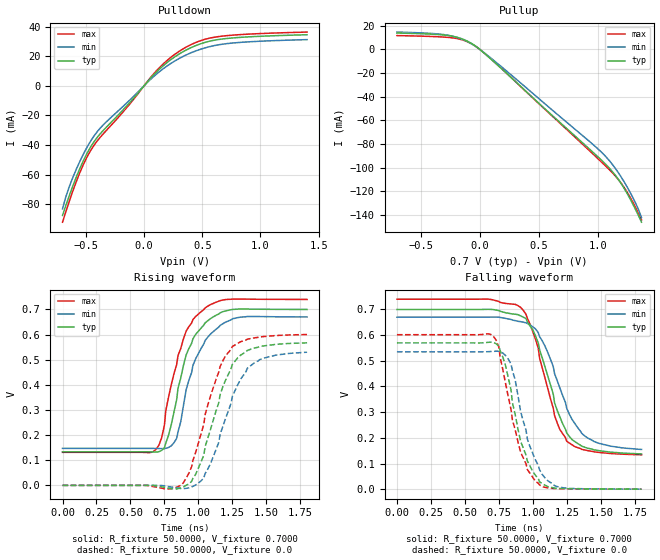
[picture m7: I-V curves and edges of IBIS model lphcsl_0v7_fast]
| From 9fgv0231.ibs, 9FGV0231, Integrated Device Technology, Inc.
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[Model]   lphcsl_0v7_fast
Model_type Output
Polarity   Non-Inverting
Enable   Active-High
Vmeas =  0.4000V
Cref =   2.0000pF
Rref =   0.0
Vref =   0.4000V
C_comp   1.1000pF   1.0000pF   1.2000pF
[Temperature Range]   25.0000   75.0000   0.0
[Voltage Range]   0.7000V   0.6700V   0.7400V
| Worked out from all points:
|   slope of the pulldown table from 0 to 0.105 V, typ, clamps not added: 11.5 ohm
|   slope of the pullup table from 0 to 0.105 V, typ, clamps not added: 11.5 ohm
|   rising waveform, R_fixture 50.0000, V_fixture 0.7000: 20-80 % time 161ps typ, 172ps min, 163ps max; typ from 0.134 V to 0.7 V
|   rising waveform, R_fixture 50.0000, V_fixture 0.0: 20-80 % time 196ps typ, 209ps min, 193ps max; typ from 0 V to 0.567 V
|   falling waveform, R_fixture 50.0000, V_fixture 0.7000: 20-80 % time 198ps typ, 226ps min, 186ps max; typ from 0.7 V to 0.138 V
|   falling waveform, R_fixture 50.0000, V_fixture 0.0: 20-80 % time 148ps typ, 157ps min, 158ps max; typ from 0.57 V to 0 V
[Pulldown]
|Voltage   I(typ)   I(min)   I(max)
-700mV    -87.46mA   -83.06mA   -92.05mA
-640mV    -73.75mA   -67.7mA    -77.54mA
-580mV    -61.27mA   -56.03mA   -64.32mA
-490mV    -45.66mA   -41.53mA   -48.1mA
-430mV    -37.82mA   -33.91mA   -40.19mA
-340mV    -29.28mA   -25.55mA   -31.55mA
50mV      4.609mA    3.896mA    5.041mA
230mV     17.65mA    15.08mA    19.19mA
410mV     26mA       22.5mA     28.05mA
590mV     30.57mA    26.92mA    32.6mA
860mV     32.86mA    29.49mA    34.71mA
1.4V      34.46mA    31.17mA    36.26mA
[Pullup]
|Voltage   I(typ)   I(min)   I(max)
-700mV    13.69mA    14.51mA    11.54mA
-370mV    12.52mA    13.09mA    10.63mA
-220mV    10.82mA    10.77mA    9.497mA
-100mV    6.649mA    6.27mA     6.197mA
-10mV     821.9uA    747.4uA    796.9uA
290mV     -26.07mA   -23.65mA   -26.13mA
1.04V     -94.6mA    -87.89mA   -96.18mA
1.13V     -104.2mA   -98.2mA    -105.1mA
1.22V     -117.1mA   -111.6mA   -116.4mA
1.31V     -133.6mA   -128mA     -131.9mA
1.34V     -139.7mA   -134.5mA   -137.9mA
1.37V     -146.2mA   -142.3mA   -144.3mA
[Ramp]
| variable   typ   min   max
dV/dt_r  0.3404/0.1944n   0.3179/0.2062n   0.3601/0.1919n
dV/dt_f  0.3375/0.1959n   0.3091/0.2218n   0.3636/0.1855n
R_load = 50.0000
[Rising Waveform]
R_fixture= 50.0000
V_fixture= 0.7000
V_fixture_min= 0.6700
V_fixture_max= 0.7400
|time   V(typ)   V(min)   V(max)
0s        133.6mV    147.2mV    131.3mV
640ps     133.6mV    147.2mV    130.1mV
730ps     139.3mV    146.3mV    190.1mV
780ps     199mV      150.6mV    350.3mV
840ps     340.8mV    187.2mV    480.7mV
910ps     519.1mV    380.8mV    613.9mV
980ps     601mV      504mV      672.2mV
1.09ns    664.1mV    602.6mV    719.7mV
1.25ns    700.2mV    662.9mV    741.4mV
1.8ns     700.2mV    670.4mV    740.1mV
[Rising Waveform]
R_fixture= 50.0000
V_fixture= 0.0
V_fixture_min= 0.0
V_fixture_max= 0.0
|time   V(typ)   V(min)   V(max)
0s        0V         0V         0V
870ps     -10.37mV   -12.56mV   -102.8uV
950ps     16.06mV    -6.886mV   73.86mV
1.04ns    120.1mV    29.51mV    243.5mV
1.07ns    189.3mV    65.39mV    320.9mV
1.16ns    361.1mV    203.1mV    473.5mV
1.25ns    481.3mV    354.1mV    552.7mV
1.36ns    537mV      466mV      581.7mV
1.42ns    547.6mV    490.7mV    587.7mV
1.8ns     567.3mV    529.9mV    600.2mV
[Falling Waveform]
R_fixture= 50.0000
V_fixture= 0.7000
V_fixture_min= 0.6700
V_fixture_max= 0.7400
|time   V(typ)   V(min)   V(max)
0s        700mV      670mV      740mV
670ps     700.5mV    670.1mV    740.3mV
910ps     675.2mV    652.5mV    708.4mV
950ps     664.7mV    647.9mV    680.9mV
1.04ns    569.5mV    609.9mV    549.2mV
1.16ns    336.4mV    450.4mV    286.8mV
1.25ns    219mV      314.3mV    186.5mV
1.36ns    167.7mV    217.5mV    155.1mV
1.45ns    153.3mV    185.8mV    145.6mV
1.8ns     137.5mV    154.9mV    134mV
[Falling Waveform]
R_fixture= 50.0000
V_fixture= 0.0
V_fixture_min= 0.0
V_fixture_max= 0.0
|time   V(typ)   V(min)   V(max)
0s        569.8mV    535.1mV    601.7mV
710ps     571.3mV    536.8mV    595.1mV
750ps     557.2mV    537.2mV    554.1mV
840ps     385.3mV    487mV      309.2mV
850ps     337.3mV    461.6mV    269.4mV
910ps     187mV      302.9mV    144.2mV
960ps     109.8mV    195mV      76.57mV
1.07ns    20.83mV    57.2mV     9.671mV
1.22ns    2.418mV    5.906mV    1.792mV
1.8ns     214uV      374.6uV    155.2uV
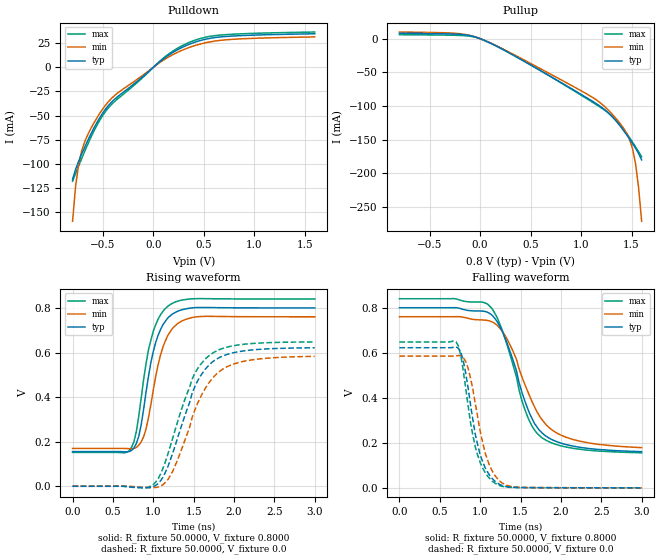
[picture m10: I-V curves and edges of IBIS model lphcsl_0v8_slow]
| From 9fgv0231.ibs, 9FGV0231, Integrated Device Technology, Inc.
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[Model]   lphcsl_0v8_slow
Model_type Output
Polarity   Non-Inverting
Enable   Active-High
Vmeas =  0.4000V
Cref =   2.0000pF
Rref =   0.0
Vref =   0.4000V
C_comp   1.1000pF   1.0000pF   1.2000pF
[Temperature Range]   25.0000   75.0000   0.0
[Voltage Range]   0.8000V   0.7600V   0.8400V
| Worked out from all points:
|   slope of the pulldown table from 0 to 0.12 V, typ, clamps not added: 11.7 ohm
|   slope of the pullup table from 0 to 0.12 V, typ, clamps not added: 14.9 ohm
|   rising waveform, R_fixture 50.0000, V_fixture 0.8000: 20-80 % time 200ps typ, 210ps min, 198ps max; typ from 0.156 V to 0.8 V
|   rising waveform, R_fixture 50.0000, V_fixture 0.0: 20-80 % time 372ps typ, 395ps min, 365ps max; typ from 0 V to 0.621 V
|   falling waveform, R_fixture 50.0000, V_fixture 0.8000: 20-80 % time 369ps typ, 426ps min, 346ps max; typ from 0.8 V to 0.161 V
|   falling waveform, R_fixture 50.0000, V_fixture 0.0: 20-80 % time 196ps typ, 206ps min, 192ps max; typ from 0.622 V to 0 V
[Pulldown]
|Voltage   I(typ)   I(min)   I(max)
-800mV    -116.2mA   -159.6mA   -118.1mA
-770mV    -105.7mA   -123.3mA   -110mA
-740mV    -97.45mA   -100.6mA   -102.3mA
-710mV    -89.96mA   -86.62mA   -94.65mA
-680mV    -82.85mA   -77.23mA   -87.18mA
-590mV    -63.31mA   -57.9mA    -66.46mA
-500mV    -47.21mA   -42.99mA   -49.67mA
-350mV    -30.12mA   -26.35mA   -32.41mA
130mV     11.06mA    9.39mA     12.07mA
430mV     26.68mA    23.13mA    28.76mA
760mV     32.3mA     28.88mA    34.18mA
1.6V      34.82mA    31.54mA    36.61mA
[Pullup]
|Voltage   I(typ)   I(min)   I(max)
-800mV    8.048mA    9.895mA    5.936mA
-230mV    6.658mA    7.836mA    4.986mA
10mV      -610.1uA   -603.7uA   -546.5uA
400mV     -30.63mA   -28.86mA   -30.13mA
1.18V     -99.5mA    -94.17mA   -100.9mA
1.36V     -124.8mA   -121.1mA   -123.5mA
1.42V     -136.4mA   -133mA     -134.6mA
1.48V     -149.1mA   -149.7mA   -147.2mA
1.51V     -155.9mA   -163.7mA   -153.9mA
1.54V     -163mA     -186.3mA   -161mA
1.57V     -170.8mA   -221.5mA   -168.2mA
1.6V      -180.3mA   -271.5mA   -175.6mA
[Ramp]
| variable   typ   min   max
dV/dt_r  0.3728/0.3923n   0.3497/0.4152n   0.3884/0.3847n
dV/dt_f  0.3835/0.3888n   0.3488/0.4461n   0.4106/0.3660n
R_load = 50.0000
[Rising Waveform]
R_fixture= 50.0000
V_fixture= 0.8000
V_fixture_min= 0.7600
V_fixture_max= 0.8400
|time   V(typ)   V(min)   V(max)
0s        155.5mV    169.8mV    151.7mV
730ps     160.5mV    168.1mV    174.2mV
790ps     191.7mV    174.2mV    245.5mV
880ps     345.2mV    221.9mV    478.6mV
940ps     492.3mV    307.8mV    611.5mV
1ns       604.4mV    431.8mV    695.9mV
1.09ns    703.3mV    589.3mV    769.4mV
1.21ns    764.5mV    693.4mV    815.4mV
1.55ns    801.8mV    760.6mV    841.7mV
3ns       800mV      760.1mV    840mV
[Rising Waveform]
R_fixture= 50.0000
V_fixture= 0.0
V_fixture_min= 0.0
V_fixture_max= 0.0
|time   V(typ)   V(min)   V(max)
0s        0V         0V         0V
1ns       -1.534mV   -6.251mV   7.313mV
1.12ns    40.5mV     7.13mV     80.44mV
1.24ns    148mV      67.05mV    215.2mV
1.48ns    416.1mV    307.4mV    479.7mV
1.61ns    508.3mV    417.9mV    556.9mV
1.76ns    565.2mV    495.3mV    602.8mV
1.91ns    590.9mV    535.7mV    623.8mV
2.15ns    608.6mV    562.6mV    638.1mV
3ns       621.3mV    582.9mV    647.4mV
[Falling Waveform]
R_fixture= 50.0000
V_fixture= 0.8000
V_fixture_min= 0.7600
V_fixture_max= 0.8400
|time   V(typ)   V(min)   V(max)
0s        800mV      760mV      840mV
1.09ns    780.1mV    743.3mV    816.4mV
1.21ns    738.8mV    721.9mV    756.9mV
1.33ns    645.9mV    662.9mV    639mV
1.55ns    389.2mV    463mV      351.4mV
1.64ns    309.7mV    385mV      275.7mV
1.73ns    257.3mV    322mV      233.7mV
1.88ns    215.9mV    259.8mV    200.5mV
2.12ns    187.6mV    218.1mV    177.5mV
3ns       160.9mV    178.7mV    155.7mV
[Falling Waveform]
R_fixture= 50.0000
V_fixture= 0.0
V_fixture_min= 0.0
V_fixture_max= 0.0
|time   V(typ)   V(min)   V(max)
0s        622.3mV    585.1mV    648mV
700ps     626mV      586.4mV    649mV
760ps     602.8mV    586.3mV    588.6mV
850ps     444.3mV    532.1mV    366.5mV
910ps     301.8mV    436mV      232.6mV
970ps     190.1mV    312.7mV    144mV
1.06ns    90.53mV    156.7mV    69.25mV
1.21ns    21.61mV    42.22mV    14.51mV
1.48ns    1.586mV    2.449mV    1.326mV
3ns       115.2uV    172.4uV    91.15uV
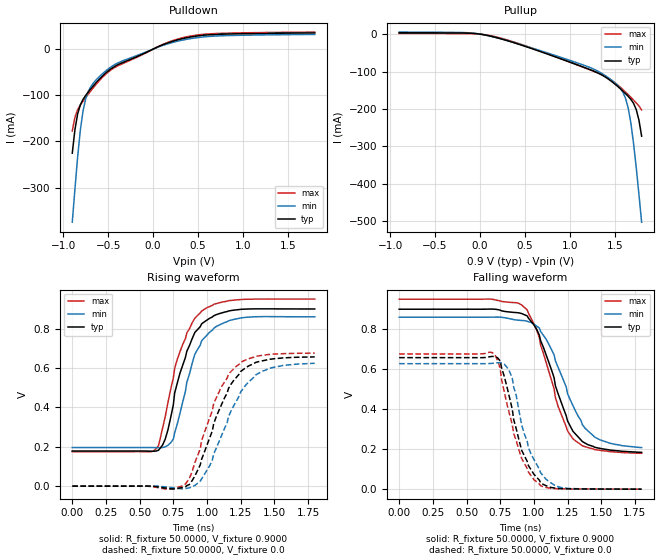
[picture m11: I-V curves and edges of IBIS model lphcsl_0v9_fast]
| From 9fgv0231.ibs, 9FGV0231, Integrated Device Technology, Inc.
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[Model]   lphcsl_0v9_fast
Model_type Output
Polarity   Non-Inverting
Enable   Active-High
Vmeas =  0.4000V
Cref =   2.0000pF
Rref =   0.0
Vref =   0.4000V
C_comp   1.1000pF   1.0000pF   1.2000pF
[Temperature Range]   25.0000   75.0000   0.0
[Voltage Range]   0.9000V   0.8600V   0.9500V
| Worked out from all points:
|   slope of the pulldown table from 0 to 0.135 V, typ, clamps not added: 11.8 ohm
|   slope of the pullup table from 0 to 0.135 V, typ, clamps not added: 21.1 ohm
|   rising waveform, R_fixture 50.0000, V_fixture 0.9000: 20-80 % time 172ps typ, 171ps min, 183ps max; typ from 0.178 V to 0.9 V
|   rising waveform, R_fixture 50.0000, V_fixture 0.0: 20-80 % time 228ps typ, 238ps min, 223ps max; typ from 0 V to 0.656 V
|   falling waveform, R_fixture 50.0000, V_fixture 0.9000: 20-80 % time 216ps typ, 245ps min, 207ps max; typ from 0.9 V to 0.184 V
|   falling waveform, R_fixture 50.0000, V_fixture 0.0: 20-80 % time 159ps typ, 165ps min, 162ps max; typ from 0.658 V to 0 V
[Pulldown]
|Voltage   I(typ)   I(min)   I(max)
-900mV    -225.6mA   -375.2mA   -177.4mA
-870mV    -174mA     -302.4mA   -147.5mA
-840mV    -140.3mA   -233.2mA   -131.2mA
-810mV    -120.8mA   -175.3mA   -121mA
-780mV    -109mA     -133.7mA   -112.8mA
-750mV    -100.2mA   -107mA     -105mA
-720mV    -92.49mA   -90.68mA   -97.27mA
-660mV    -78.35mA   -72.31mA   -82.41mA
-510mV    -48.82mA   -44.52mA   -51.32mA
90mV      7.972mA    6.753mA    8.709mA
390mV     25.27mA    21.84mA    27.29mA
1.8V      35.12mA    31.84mA    36.91mA
[Pullup]
|Voltage   I(typ)   I(min)   I(max)
-900mV    3.551mA    5.396mA    1.738mA
-150mV    2.686mA    3.793mA    1.334mA
150mV     -7.265mA   -7.528mA   -5.877mA
1.17V     -89.91mA   -84.27mA   -90.34mA
1.47V     -127.4mA   -123.7mA   -124.2mA
1.59V     -152mA     -154.4mA   -147.8mA
1.62V     -158.9mA   -170.8mA   -154.6mA
1.65V     -166.1mA   -197.2mA   -161.6mA
1.68V     -174.3mA   -237.1mA   -168.8mA
1.74V     -201.6mA   -356.7mA   -183.8mA
1.77V     -229.7mA   -428mA     -192mA
1.8V      -272.8mA   -502.6mA   -202.5mA
[Ramp]
| variable   typ   min   max
dV/dt_r  0.3939/0.2244n   0.3744/0.2413n   0.4055/0.2185n
dV/dt_f  0.4294/0.2165n   0.3912/0.2409n   0.4624/0.2039n
R_load = 50.0000
[Rising Waveform]
R_fixture= 50.0000
V_fixture= 0.9000
V_fixture_min= 0.8600
V_fixture_max= 0.9500
|time   V(typ)   V(min)   V(max)
0s        178.3mV    195.9mV    175.1mV
620ps     177.9mV    195.5mV    188.5mV
690ps     238.7mV    199.7mV    352.1mV
750ps     412.4mV    238.8mV    548.8mV
760ps     472.7mV    270.1mV    598.4mV
850ps     684.8mV    526.9mV    778.5mV
910ps     781.1mV    670.6mV    853.4mV
980ps     834.5mV    752.9mV    898.2mV
1.25ns    898.3mV    854.7mV    948.1mV
1.8ns     900.1mV    860.3mV    950.1mV
[Rising Waveform]
R_fixture= 50.0000
V_fixture= 0.0
V_fixture_min= 0.0
V_fixture_max= 0.0
|time   V(typ)   V(min)   V(max)
0s        0V         0V         0V
750ps     -14.92mV   -8.628mV   -12.15mV
840ps     -3.604mV   -12.95mV   10.59mV
910ps     51.49mV    3.362mV    120mV
1.02ns    244.9mV    103.2mV    347mV
1.05ns    318mV      163.9mV    420.2mV
1.16ns    496.7mV    353.7mV    569.9mV
1.25ns    582.6mV    478.9mV    627.9mV
1.45ns    643.1mV    595.7mV    668.4mV
1.8ns     656.5mV    624mV      675.8mV
[Falling Waveform]
R_fixture= 50.0000
V_fixture= 0.9000
V_fixture_min= 0.8600
V_fixture_max= 0.9500
|time   V(typ)   V(min)   V(max)
0s        900mV      860mV      950mV
670ps     900.6mV    860.1mV    950.7mV
910ps     878.1mV    843.6mV    920.9mV
1.02ns    800mV      815.8mV    797.7mV
1.09ns    673.8mV    751.2mV    636.5mV
1.18ns    477.3mV    609.4mV    414.4mV
1.29ns    289.7mV    418.3mV    252.4mV
1.36ns    238.1mV    323mV      216.9mV
1.45ns    210mV      261.3mV    198.4mV
1.8ns     184.3mV    208mV      179.4mV
[Falling Waveform]
R_fixture= 50.0000
V_fixture= 0.0
V_fixture_min= 0.0
V_fixture_max= 0.0
|time   V(typ)   V(min)   V(max)
0s        657.8mV    627.8mV    676.3mV
690ps     663.9mV    629.2mV    683.3mV
750ps     641.1mV    632.5mV    604.2mV
780ps     565.1mV    625mV      488.6mV
840ps     399.3mV    554.1mV    320.6mV
910ps     193.9mV    320.3mV    153.3mV
980ps     96.4mV     174.5mV    66.94mV
1.09ns    17.81mV    49.88mV    8.918mV
1.25ns    2.02mV     4.257mV    1.557mV
1.8ns     223.5uV    398.4uV    162.8uV
